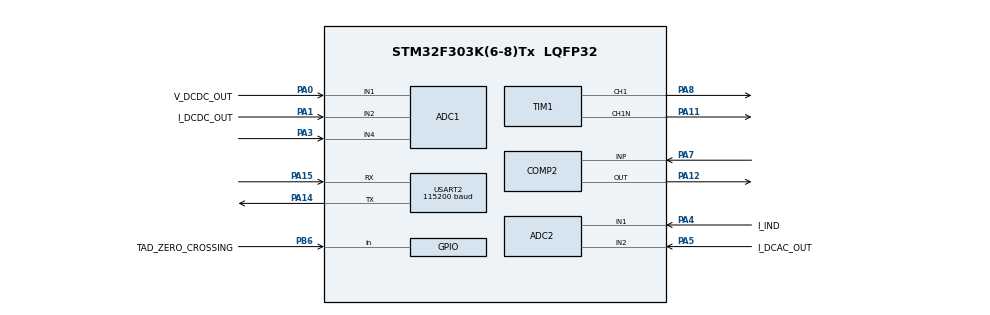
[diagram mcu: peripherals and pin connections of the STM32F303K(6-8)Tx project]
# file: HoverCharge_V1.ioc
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ADC1.Channel-3\#ChannelRegularConversion=ADC_CHANNEL_1
ADC1.Channel-4\#ChannelRegularConversion=ADC_CHANNEL_1
ADC1.ClockPrescaler=ADC_CLOCK_SYNC_PCLK_DIV1
ADC1.DMAContinuousRequests=ENABLE
ADC1.ExternalTrigConv=ADC_EXTERNALTRIGCONV_T1_TRGO
ADC1.NbrOfConversion=2
ADC1.NbrOfConversionFlag=1
ADC1.Offset-3\#ChannelRegularConversion=0
ADC1.Offset-4\#ChannelRegularConversion=0
ADC1.OffsetNumber-3\#ChannelRegularConversion=ADC_OFFSET_NONE
ADC1.OffsetNumber-4\#ChannelRegularConversion=ADC_OFFSET_NONE
ADC1.Rank-3\#ChannelRegularConversion=1
ADC1.Rank-4\#ChannelRegularConversion=2
ADC1.SamplingTime-3\#ChannelRegularConversion=ADC_SAMPLETIME_1CYCLE_5
ADC1.SamplingTime-4\#ChannelRegularConversion=ADC_SAMPLETIME_1CYCLE_5
ADC1.SubFamily=STM32F303x8
ADC1.master=1
ADC2.Channel-2\#ChannelRegularConversion=ADC_CHANNEL_1
ADC2.Channel-3\#ChannelRegularConversion=ADC_CHANNEL_1
ADC2.ClockPrescaler=ADC_CLOCK_SYNC_PCLK_DIV1
ADC2.DMAContinuousRequests=ENABLE
ADC2.ExternalTrigConv=ADC_EXTERNALTRIGCONV_T1_TRGO
ADC2.NbrOfConversion=2
ADC2.NbrOfConversionFlag=1
ADC2.Offset-2\#ChannelRegularConversion=0
ADC2.Offset-3\#ChannelRegularConversion=0
ADC2.OffsetNumber-2\#ChannelRegularConversion=ADC_OFFSET_NONE
ADC2.OffsetNumber-3\#ChannelRegularConversion=ADC_OFFSET_NONE
ADC2.Rank-2\#ChannelRegularConversion=1
ADC2.Rank-3\#ChannelRegularConversion=2
ADC2.SamplingTime-2\#ChannelRegularConversion=ADC_SAMPLETIME_1CYCLE_5
ADC2.SamplingTime-3\#ChannelRegularConversion=ADC_SAMPLETIME_1CYCLE_5
ADC2.SamplingTimeOPAMP-3\#ChannelRegularConversion=ADC_SAMPLETIME_61CYCLES_5
ADC2.SubFamily=STM32F303x8
Dma.ADC1.0.Direction=DMA_PERIPH_TO_MEMORY
Dma.ADC1.0.Instance=DMA1_Channel1
Dma.ADC1.0.MemDataAlignment=DMA_MDATAALIGN_WORD
Dma.ADC1.0.MemInc=DMA_MINC_ENABLE
Dma.ADC1.0.Mode=DMA_CIRCULAR
Dma.ADC1.0.PeriphDataAlignment=DMA_PDATAALIGN_WORD
Dma.ADC1.0.PeriphInc=DMA_PINC_DISABLE
Dma.ADC1.0.Priority=DMA_PRIORITY_LOW
Dma.ADC2.1.Direction=DMA_PERIPH_TO_MEMORY
Dma.ADC2.1.Instance=DMA1_Channel2
Dma.ADC2.1.MemDataAlignment=DMA_MDATAALIGN_WORD
Dma.ADC2.1.MemInc=DMA_MINC_ENABLE
Dma.ADC2.1.Mode=DMA_CIRCULAR
Dma.ADC2.1.PeriphDataAlignment=DMA_PDATAALIGN_WORD
Dma.ADC2.1.PeriphInc=DMA_PINC_DISABLE
Dma.ADC2.1.Priority=DMA_PRIORITY_LOW
Dma.Request0=ADC1
Dma.Request1=ADC2
Mcu.Family=STM32F3
Mcu.Name=STM32F303K(6-8)Tx
Mcu.Package=LQFP32
NVIC.DMA1_Channel1_IRQn=true\:0\:0\:false\:false\:true\:false\:true\:true
NVIC.DMA1_Channel2_IRQn=true\:0\:0\:false\:false\:true\:false\:true\:true
NVIC.PriorityGroup=NVIC_PRIORITYGROUP_4
PA0.GPIO_Label=V_DCDC_OUT
PA0.Mode=IN1-Single-Ended
PA0.Signal=ADC1_IN1
PA1.GPIO_Label=I_DCDC_OUT
PA1.Mode=IN2-Single-Ended
PA1.Signal=ADC1_IN2
PA11.Mode=PWM Generation1 CH1 CH1N
PA11.Signal=TIM1_CH1N
PA12.Mode=ExternalOutput
PA12.Signal=COMP2_OUT
PA14.Mode=Asynchronous
PA14.Signal=USART2_TX
PA15.Mode=Asynchronous
PA15.Signal=USART2_RX
PA3.Mode=IN4-Single-Ended
PA3.Signal=ADC1_IN4
PA4.GPIO_Label=I_IND
PA4.Mode=IN1-Single-Ended
PA4.Signal=ADC2_IN1
PA5.GPIO_Label=I_DCAC_OUT
PA5.Mode=IN2-Single-Ended
PA5.Signal=ADC2_IN2
PA7.Mode=INP
PA7.Signal=COMP2_INP
PA8.Signal=S_TIM1_CH1
PB6.GPIO_Label=TAD_ZERO_CROSSING
PB6.Signal=GPIO_Input
ProjectManager.HeapSize=0x200
ProjectManager.StackSize=0x400
ProjectManager.TargetToolchain=STM32CubeIDE
RCC.AHBCLKDivider=RCC_SYSCLK_DIV256
RCC.AHBFreq_Value=250000
RCC.APB1CLKDivider=RCC_HCLK_DIV2
RCC.APB1Freq_Value=125000
RCC.APB1TimFreq_Value=250000
RCC.APB2Freq_Value=250000
RCC.APB2TimFreq_Value=250000
RCC.CortexFreq_Value=250000
RCC.HCLKFreq_Value=250000
RCC.HSE_VALUE=8000000
RCC.HSI_VALUE=8000000
RCC.PLLMUL=RCC_PLL_MUL16
RCC.SYSCLKFreq_VALUE=64000000
RCC.SYSCLKSourceVirtual=RCC_SYSCLKSOURCE_PLLCLK
SH.S_TIM1_CH1.0=TIM1_CH1,PWM Generation1 CH1 CH1N
TIM1.Channel-PWM\ Generation1\ CH1\ CH1N=TIM_CHANNEL_1
TIM1.CounterMode=TIM_COUNTERMODE_UP
TIM1.DeadTime=50
TIM1.RepetitionCounter=1
TIM1.TIM_MasterOutputTrigger=TIM_TRGO_UPDATE
USART2.BaudRate=115200
USART2.VirtualMode-Asynchronous=VM_ASYNC
board=custom

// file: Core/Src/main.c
/* USER CODE BEGIN Header */
/**
  ******************************************************************************
  * @file           : main.c
  * @brief          : Main program body
  ******************************************************************************
  * @attention
  *
  * Copyright (c) 2024 STMicroelectronics.
  * All rights reserved.
  *
  * This software is licensed under terms that can be found in the LICENSE file
  * in the root directory of this software component.
  * If no LICENSE file comes with this software, it is provided AS-IS.
  *
  ******************************************************************************
  */
/* USER CODE END Header */
#include "main.h"

/* USER CODE BEGIN Includes */
#include "stdlib.h"
#include "stdio.h"
#include "string.h"

/* USER CODE END Includes */

ADC_HandleTypeDef hadc1;
ADC_HandleTypeDef hadc2;
DMA_HandleTypeDef hdma_adc1;
DMA_HandleTypeDef hdma_adc2;

TIM_HandleTypeDef htim1;

UART_HandleTypeDef huart2;

/* USER CODE BEGIN PV */
uint8_t TxStartMessage[] = "/r/n***** Group 1 - HoverCharge - 5XWF0 *****/r/n";

//ADC
uint32_t ADC1_Buff[3];
uint32_t ADC2_Buff[2];

uint32_t adc_val_1;
float V_DCDC_OUT=0.0f;

uint32_t adc_val_2;
float I_DCDC_OUT=0.0f;

uint32_t adc_val_3;
float V_DCDC_IN=0.0f;

uint32_t adc_val_4;
float I_IND=0.0f;

uint32_t adc_val_5;
float I_DCAC_OUT=0.0f;
//PWM
uint32_t PWM_Freq = 100000;
float PWM_DutyC_DCDC = 25;
float PWM_DutyC_DCAC = 75;
int32_t PWM_Period;
int32_t PWM_PulseWidth_DCDC;
int32_t PWM_PulseWidth_DCAC;

/* USER CODE END PV */

void SystemClock_Config(void);
static void MX_GPIO_Init(void);
static void MX_DMA_Init(void);
static void MX_USART2_UART_Init(void);
static void MX_TIM1_Init(void);
static void MX_ADC1_Init(void);
static void MX_ADC2_Init(void);

/* USER CODE BEGIN 0 */
#ifdef __GNUC__
	#define PUTCHAR_PROTOTYPE int __io_putchar(int ch)
#else
	#define PUTCHAR_PROTOTYPE int fputc(int ch, FILE *f)
#endif

PUTCHAR_PROTOTYPE
{
	HAL_UART_Transmit(&huart2, (uint8_t *)&ch, 1, 0xFFF);

	return ch;
}
/* USER CODE END 0 */

int main(void)
{

  /* MCU Configuration--------------------------------------------------------*/

  /* Reset of all peripherals, Initializes the Flash interface and the Systick. */
  HAL_Init();

  /* Configure the system clock */
  SystemClock_Config();

  /* Initialize all configured peripherals */
  MX_GPIO_Init();
  MX_DMA_Init();
  MX_USART2_UART_Init();
  MX_TIM1_Init();
  MX_ADC1_Init();
  MX_ADC2_Init();
  /* USER CODE BEGIN 2 */
   printf("%s", TxStartMessage);

   PWM_Period = 64000000/(2*PWM_Freq)-1;
   PWM_PulseWidth_DCAC = (int)((PWM_Period*PWM_DutyC_DCAC)/100);
   PWM_PulseWidth_DCDC = (int)((PWM_Period*PWM_DutyC_DCDC)/100);

   __HAL_TIM_SET_AUTORELOAD(&htim1, PWM_Period);					//Timer 1 config

   __HAL_TIM_SET_COMPARE(&htim1, TIM_CHANNEL_1, PWM_PulseWidth_DCAC);	//Tim1 Channel 1 config
   HAL_TIM_PWM_Start(&htim1, TIM_CHANNEL_1);
   HAL_TIMEx_PWMN_Start(&htim1, TIM_CHANNEL_1);

    __HAL_TIM_SET_COMPARE(&htim1, TIM_CHANNEL_4, PWM_PulseWidth_DCDC);	//Tim1 Channel 4 config
    HAL_TIM_PWM_Start(&htim1, TIM_CHANNEL_4);

   HAL_ADCEx_Calibration_Start(&hadc1, ADC_SINGLE_ENDED);				//ADC1 config
   HAL_ADC_Start_DMA(&hadc1, (uint32_t*)ADC1_Buff, 3);

   HAL_ADCEx_Calibration_Start(&hadc2, ADC_SINGLE_ENDED);				//ADC2 config
   HAL_ADC_Start_DMA(&hadc2, (uint32_t*)ADC2_Buff, 2);

  /* USER CODE BEGIN 2 */

  /* USER CODE END 2 */

  /* Infinite loop */
  /* USER CODE BEGIN WHILE */
  while (1)
  {
	  PWM_DutyC_DCDC = V_DCDC_OUT*111.11f;
	  PWM_DutyC_DCAC = I_DCAC_OUT*111.11f;
	  // Conversion range 0-0.9V to 0-100%
	  PWM_PulseWidth_DCDC = (int)((PWM_Period * PWM_DutyC_DCDC)/100); //Hier is iets fout
	  __HAL_TIM_SET_COMPARE (&htim1, TIM_CHANNEL_4, PWM_PulseWidth_DCDC);

	  //PWM_PulseWidth_DCAC = (int)((PWM_Period * PWM_DutyC_DCAC)/100); //Hier is iets fout
	  __HAL_TIM_SET_COMPARE (&htim1, TIM_CHANNEL_1, PWM_PulseWidth_DCAC);
	  printf("ADC Voltage DCDC: %.2f V Duty Cycle %.2f\r\n ADC Voltage DCAC: %.2f V Duty Cycle %.2f\r\n", V_DCDC_OUT, PWM_DutyC_DCDC,I_DCAC_OUT, PWM_DutyC_DCAC);
	  HAL_Delay(500);
    /* USER CODE END WHILE */

  }
}

void SystemClock_Config(void)
{
  RCC_OscInitTypeDef RCC_OscInitStruct = {0};
  RCC_ClkInitTypeDef RCC_ClkInitStruct = {0};
  RCC_PeriphCLKInitTypeDef PeriphClkInit = {0};

  /** Initializes the RCC Oscillators according to the specified parameters
  * in the RCC_OscInitTypeDef structure.
  */
  RCC_OscInitStruct.OscillatorType = RCC_OSCILLATORTYPE_HSI;
  RCC_OscInitStruct.HSIState = RCC_HSI_ON;
  RCC_OscInitStruct.HSICalibrationValue = RCC_HSICALIBRATION_DEFAULT;
  RCC_OscInitStruct.PLL.PLLState = RCC_PLL_ON;
  RCC_OscInitStruct.PLL.PLLSource = RCC_PLLSOURCE_HSI;
  RCC_OscInitStruct.PLL.PLLMUL = RCC_PLL_MUL16;
  if (HAL_RCC_OscConfig(&RCC_OscInitStruct) != HAL_OK)
  {
    Error_Handler();
  }

  /** Initializes the CPU, AHB and APB buses clocks
  */
  RCC_ClkInitStruct.ClockType = RCC_CLOCKTYPE_HCLK|RCC_CLOCKTYPE_SYSCLK
                              |RCC_CLOCKTYPE_PCLK1|RCC_CLOCKTYPE_PCLK2;
  RCC_ClkInitStruct.SYSCLKSource = RCC_SYSCLKSOURCE_PLLCLK;
  RCC_ClkInitStruct.AHBCLKDivider = RCC_SYSCLK_DIV1;
  RCC_ClkInitStruct.APB1CLKDivider = RCC_HCLK_DIV2;
  RCC_ClkInitStruct.APB2CLKDivider = RCC_HCLK_DIV1;

  if (HAL_RCC_ClockConfig(&RCC_ClkInitStruct, FLASH_LATENCY_2) != HAL_OK)
  {
    Error_Handler();
  }
  PeriphClkInit.PeriphClockSelection = RCC_PERIPHCLK_TIM1;
  PeriphClkInit.Tim1ClockSelection = RCC_TIM1CLK_HCLK;
  if (HAL_RCCEx_PeriphCLKConfig(&PeriphClkInit) != HAL_OK)
  {
    Error_Handler();
  }
}

static void MX_ADC1_Init(void)
{

  ADC_MultiModeTypeDef multimode = {0};
  ADC_ChannelConfTypeDef sConfig = {0};

  /** Common config
  */
  hadc1.Instance = ADC1;
  hadc1.Init.ClockPrescaler = ADC_CLOCK_SYNC_PCLK_DIV1;
  hadc1.Init.Resolution = ADC_RESOLUTION_12B;
  hadc1.Init.ScanConvMode = ADC_SCAN_ENABLE;
  hadc1.Init.ContinuousConvMode = DISABLE;
  hadc1.Init.DiscontinuousConvMode = DISABLE;
  hadc1.Init.ExternalTrigConvEdge = ADC_EXTERNALTRIGCONVEDGE_RISING;
  hadc1.Init.ExternalTrigConv = ADC_EXTERNALTRIGCONV_T1_TRGO;
  hadc1.Init.DataAlign = ADC_DATAALIGN_RIGHT;
  hadc1.Init.NbrOfConversion = 2;
  hadc1.Init.DMAContinuousRequests = ENABLE;
  hadc1.Init.EOCSelection = ADC_EOC_SINGLE_CONV;
  hadc1.Init.LowPowerAutoWait = DISABLE;
  hadc1.Init.Overrun = ADC_OVR_DATA_OVERWRITTEN;
  if (HAL_ADC_Init(&hadc1) != HAL_OK)
  {
    Error_Handler();
  }

  /** Configure the ADC multi-mode
  */
  multimode.Mode = ADC_MODE_INDEPENDENT;
  if (HAL_ADCEx_MultiModeConfigChannel(&hadc1, &multimode) != HAL_OK)
  {
    Error_Handler();
  }

  /** Configure Regular Channel
  */
  sConfig.Channel = ADC_CHANNEL_1;
  sConfig.Rank = ADC_REGULAR_RANK_1;
  sConfig.SingleDiff = ADC_SINGLE_ENDED;
  sConfig.SamplingTime = ADC_SAMPLETIME_1CYCLE_5;
  sConfig.OffsetNumber = ADC_OFFSET_NONE;
  sConfig.Offset = 0;
  if (HAL_ADC_ConfigChannel(&hadc1, &sConfig) != HAL_OK)
  {
    Error_Handler();
  }

  /** Configure Regular Channel
  */
  sConfig.Rank = ADC_REGULAR_RANK_2;
  if (HAL_ADC_ConfigChannel(&hadc1, &sConfig) != HAL_OK)
  {
    Error_Handler();
  }

}

static void MX_ADC2_Init(void)
{

  ADC_ChannelConfTypeDef sConfig = {0};

  /** Common config
  */
  hadc2.Instance = ADC2;
  hadc2.Init.ClockPrescaler = ADC_CLOCK_SYNC_PCLK_DIV1;
  hadc2.Init.Resolution = ADC_RESOLUTION_12B;
  hadc2.Init.ScanConvMode = ADC_SCAN_ENABLE;
  hadc2.Init.ContinuousConvMode = DISABLE;
  hadc2.Init.DiscontinuousConvMode = DISABLE;
  hadc2.Init.ExternalTrigConvEdge = ADC_EXTERNALTRIGCONVEDGE_RISING;
  hadc2.Init.ExternalTrigConv = ADC_EXTERNALTRIGCONV_T1_TRGO;
  hadc2.Init.DataAlign = ADC_DATAALIGN_RIGHT;
  hadc2.Init.NbrOfConversion = 2;
  hadc2.Init.DMAContinuousRequests = ENABLE;
  hadc2.Init.EOCSelection = ADC_EOC_SINGLE_CONV;
  hadc2.Init.LowPowerAutoWait = DISABLE;
  hadc2.Init.Overrun = ADC_OVR_DATA_OVERWRITTEN;
  if (HAL_ADC_Init(&hadc2) != HAL_OK)
  {
    Error_Handler();
  }

  /** Configure Regular Channel
  */
  sConfig.Channel = ADC_CHANNEL_1;
  sConfig.Rank = ADC_REGULAR_RANK_1;
  sConfig.SingleDiff = ADC_SINGLE_ENDED;
  sConfig.SamplingTime = ADC_SAMPLETIME_1CYCLE_5;
  sConfig.OffsetNumber = ADC_OFFSET_NONE;
  sConfig.Offset = 0;
  if (HAL_ADC_ConfigChannel(&hadc2, &sConfig) != HAL_OK)
  {
    Error_Handler();
  }

  /** Configure Regular Channel
  */
  sConfig.Rank = ADC_REGULAR_RANK_2;
  if (HAL_ADC_ConfigChannel(&hadc2, &sConfig) != HAL_OK)
  {
    Error_Handler();
  }

}

static void MX_TIM1_Init(void)
{

  TIM_ClockConfigTypeDef sClockSourceConfig = {0};
  TIM_MasterConfigTypeDef sMasterConfig = {0};
  TIM_OC_InitTypeDef sConfigOC = {0};
  TIM_BreakDeadTimeConfigTypeDef sBreakDeadTimeConfig = {0};

  htim1.Instance = TIM1;
  htim1.Init.Prescaler = 0;
  htim1.Init.CounterMode = TIM_COUNTERMODE_UP;
  htim1.Init.Period = 65535;
  htim1.Init.ClockDivision = TIM_CLOCKDIVISION_DIV1;
  htim1.Init.RepetitionCounter = 1;
  htim1.Init.AutoReloadPreload = TIM_AUTORELOAD_PRELOAD_DISABLE;
  if (HAL_TIM_Base_Init(&htim1) != HAL_OK)
  {
    Error_Handler();
  }
  sClockSourceConfig.ClockSource = TIM_CLOCKSOURCE_INTERNAL;
  if (HAL_TIM_ConfigClockSource(&htim1, &sClockSourceConfig) != HAL_OK)
  {
    Error_Handler();
  }
  if (HAL_TIM_PWM_Init(&htim1) != HAL_OK)
  {
    Error_Handler();
  }
  sMasterConfig.MasterOutputTrigger = TIM_TRGO_UPDATE;
  sMasterConfig.MasterOutputTrigger2 = TIM_TRGO2_RESET;
  sMasterConfig.MasterSlaveMode = TIM_MASTERSLAVEMODE_DISABLE;
  if (HAL_TIMEx_MasterConfigSynchronization(&htim1, &sMasterConfig) != HAL_OK)
  {
    Error_Handler();
  }
  sConfigOC.OCMode = TIM_OCMODE_PWM1;
  sConfigOC.Pulse = 0;
  sConfigOC.OCPolarity = TIM_OCPOLARITY_HIGH;
  sConfigOC.OCNPolarity = TIM_OCNPOLARITY_HIGH;
  sConfigOC.OCFastMode = TIM_OCFAST_DISABLE;
  sConfigOC.OCIdleState = TIM_OCIDLESTATE_RESET;
  sConfigOC.OCNIdleState = TIM_OCNIDLESTATE_RESET;
  if (HAL_TIM_PWM_ConfigChannel(&htim1, &sConfigOC, TIM_CHANNEL_1) != HAL_OK)
  {
    Error_Handler();
  }
  sBreakDeadTimeConfig.OffStateRunMode = TIM_OSSR_DISABLE;
  sBreakDeadTimeConfig.OffStateIDLEMode = TIM_OSSI_DISABLE;
  sBreakDeadTimeConfig.LockLevel = TIM_LOCKLEVEL_OFF;
  sBreakDeadTimeConfig.DeadTime = 50;
  sBreakDeadTimeConfig.BreakState = TIM_BREAK_DISABLE;
  sBreakDeadTimeConfig.BreakPolarity = TIM_BREAKPOLARITY_HIGH;
  sBreakDeadTimeConfig.BreakFilter = 0;
  sBreakDeadTimeConfig.Break2State = TIM_BREAK2_DISABLE;
  sBreakDeadTimeConfig.Break2Polarity = TIM_BREAK2POLARITY_HIGH;
  sBreakDeadTimeConfig.Break2Filter = 0;
  sBreakDeadTimeConfig.AutomaticOutput = TIM_AUTOMATICOUTPUT_DISABLE;
  if (HAL_TIMEx_ConfigBreakDeadTime(&htim1, &sBreakDeadTimeConfig) != HAL_OK)
  {
    Error_Handler();
  }
  HAL_TIM_MspPostInit(&htim1);

}

static void MX_USART2_UART_Init(void)
{

  huart2.Instance = USART2;
  huart2.Init.BaudRate = 115200;
  huart2.Init.WordLength = UART_WORDLENGTH_8B;
  huart2.Init.StopBits = UART_STOPBITS_1;
  huart2.Init.Parity = UART_PARITY_NONE;
  huart2.Init.Mode = UART_MODE_TX_RX;
  huart2.Init.HwFlowCtl = UART_HWCONTROL_NONE;
  huart2.Init.OverSampling = UART_OVERSAMPLING_16;
  huart2.Init.OneBitSampling = UART_ONE_BIT_SAMPLE_DISABLE;
  huart2.AdvancedInit.AdvFeatureInit = UART_ADVFEATURE_NO_INIT;
  if (HAL_UART_Init(&huart2) != HAL_OK)
  {
    Error_Handler();
  }

}

static void MX_DMA_Init(void)
{

  /* DMA controller clock enable */
  __HAL_RCC_DMA1_CLK_ENABLE();

  /* DMA interrupt init */
  /* DMA1_Channel1_IRQn interrupt configuration */
  HAL_NVIC_SetPriority(DMA1_Channel1_IRQn, 0, 0);
  HAL_NVIC_EnableIRQ(DMA1_Channel1_IRQn);
  /* DMA1_Channel2_IRQn interrupt configuration */
  HAL_NVIC_SetPriority(DMA1_Channel2_IRQn, 0, 0);
  HAL_NVIC_EnableIRQ(DMA1_Channel2_IRQn);

}

static void MX_GPIO_Init(void)
{
  GPIO_InitTypeDef GPIO_InitStruct = {0};

  /* GPIO Ports Clock Enable */
  __HAL_RCC_GPIOA_CLK_ENABLE();
  __HAL_RCC_GPIOB_CLK_ENABLE();

  /*Configure GPIO pin : TAD_ZERO_CROSSING_Pin */
  GPIO_InitStruct.Pin = TAD_ZERO_CROSSING_Pin;
  GPIO_InitStruct.Mode = GPIO_MODE_INPUT;
  GPIO_InitStruct.Pull = GPIO_NOPULL;
  HAL_GPIO_Init(TAD_ZERO_CROSSING_GPIO_Port, &GPIO_InitStruct);

}

/* USER CODE BEGIN 4 */
void HAL_ADC_ConvCpltCallback(ADC_HandleTypeDef* hadc)
{
	UNUSED(hadc);

		adc_val_1 = ADC1_Buff[0];
		V_DCDC_OUT = (((float)adc_val_1)/4095.0f)*3.3f;

		adc_val_2 = ADC1_Buff[1];
		I_DCDC_OUT = (((float)adc_val_2)/4095.0f)*3.3f;

		adc_val_3 = ADC1_Buff[2];
		V_DCDC_IN = (((float)adc_val_3)/4095.0f)*3.3f;

		adc_val_4 = ADC2_Buff[0];
		I_IND = (((float)adc_val_4)/4095.0f)*3.3f;

		adc_val_5 = ADC2_Buff[1];
		I_DCAC_OUT = (((float)adc_val_5)/4095.0f)*3.3f;
}
/* USER CODE END 4 */

void Error_Handler(void)
{
  __disable_irq();
  while (1)
  {
  }
}
